VERSION 5.7 ;
  NOWIREEXTENSIONATPIN ON ;
  DIVIDERCHAR "/" ;
  BUSBITCHARS "[]" ;
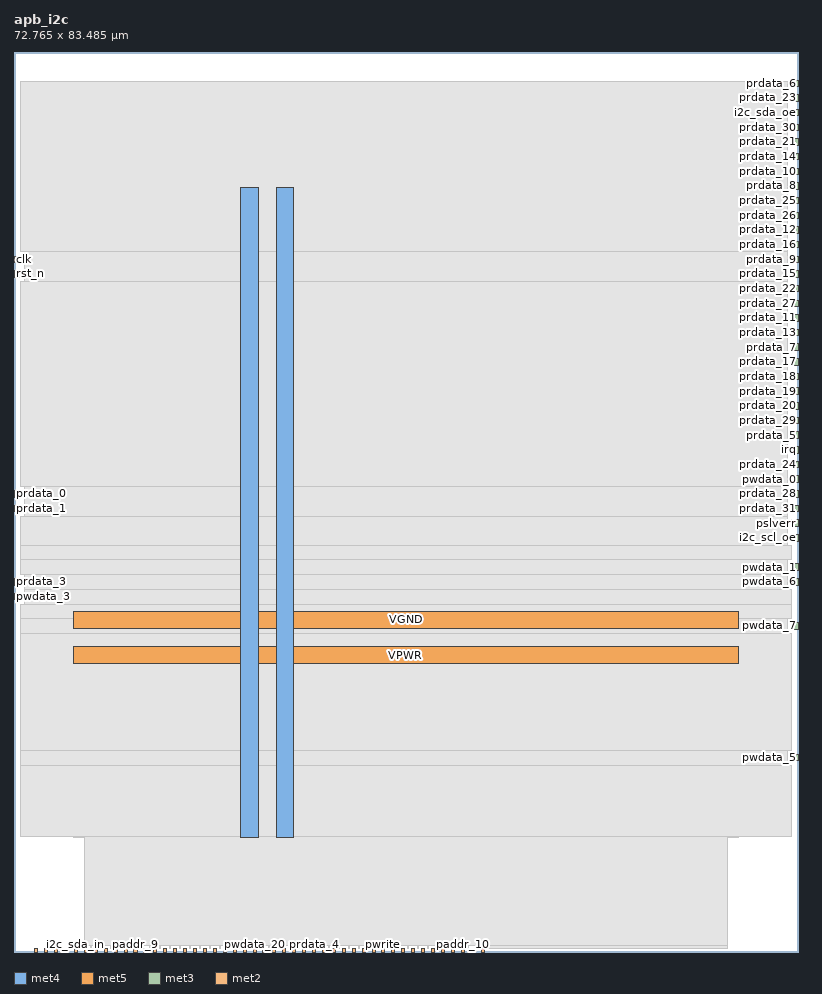
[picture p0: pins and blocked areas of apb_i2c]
MACRO apb_i2c
  CLASS BLOCK ;
  FOREIGN apb_i2c ;
  ORIGIN 0.000 0.000 ;
  SIZE 72.765 BY 83.485 ;
  PIN VGND
    DIRECTION INOUT ;
    USE GROUND ;
    PORT
      LAYER met4 ;
        RECT 24.340 10.640 25.940 70.960 ;
    END
    PORT
      LAYER met5 ;
        RECT 5.520 30.030 67.160 31.630 ;
    END
  END VGND
  PIN VPWR
    DIRECTION INOUT ;
    USE POWER ;
    PORT
      LAYER met4 ;
        RECT 21.040 10.640 22.640 70.960 ;
    END
    PORT
      LAYER met5 ;
        RECT 5.520 26.730 67.160 28.330 ;
    END
  END VPWR
  PIN clk
    DIRECTION INPUT ;
    USE SIGNAL ;
    ANTENNAGATEAREA 1.286700 ;
    ANTENNADIFFAREA 0.434700 ;
    PORT
      LAYER met3 ;
        RECT 0.000 63.960 0.600 64.560 ;
    END
  END clk
  PIN i2c_scl_in
    DIRECTION INPUT ;
    USE SIGNAL ;
    PORT
      LAYER met2 ;
        RECT 2.850 0.000 3.130 0.280 ;
    END
  END i2c_scl_in
  PIN i2c_scl_oe
    DIRECTION OUTPUT ;
    USE SIGNAL ;
    ANTENNAGATEAREA 0.434700 ;
    ANTENNADIFFAREA 0.775300 ;
    PORT
      LAYER met3 ;
        RECT 72.165 38.120 72.765 38.720 ;
    END
  END i2c_scl_oe
  PIN i2c_sda_in
    DIRECTION INPUT ;
    USE SIGNAL ;
    PORT
      LAYER met2 ;
        RECT 5.610 0.000 5.890 0.280 ;
    END
  END i2c_sda_in
  PIN i2c_sda_oe
    DIRECTION OUTPUT ;
    USE SIGNAL ;
    ANTENNAGATEAREA 0.434700 ;
    ANTENNADIFFAREA 0.775300 ;
    PORT
      LAYER met3 ;
        RECT 72.165 77.560 72.765 78.160 ;
    END
  END i2c_sda_oe
  PIN irq
    DIRECTION OUTPUT ;
    USE SIGNAL ;
    ANTENNAGATEAREA 0.434700 ;
    ANTENNADIFFAREA 1.137600 ;
    PORT
      LAYER met3 ;
        RECT 72.165 46.280 72.765 46.880 ;
    END
  END irq
  PIN paddr_0
    DIRECTION INPUT ;
    USE SIGNAL ;
    PORT
      LAYER met2 ;
        RECT 4.690 0.000 4.970 0.280 ;
    END
  END paddr_0
  PIN paddr_1
    DIRECTION INPUT ;
    USE SIGNAL ;
    PORT
      LAYER met2 ;
        RECT 7.450 0.000 7.730 0.280 ;
    END
  END paddr_1
  PIN paddr_10
    DIRECTION INPUT ;
    USE SIGNAL ;
    PORT
      LAYER met2 ;
        RECT 41.490 0.000 41.770 0.280 ;
    END
  END paddr_10
  PIN paddr_11
    DIRECTION INPUT ;
    USE SIGNAL ;
    PORT
      LAYER met2 ;
        RECT 6.530 0.000 6.810 0.280 ;
    END
  END paddr_11
  PIN paddr_2
    DIRECTION INPUT ;
    USE SIGNAL ;
    ANTENNAGATEAREA 0.647700 ;
    ANTENNADIFFAREA 0.434700 ;
    PORT
      LAYER met2 ;
        RECT 39.650 0.000 39.930 0.280 ;
    END
  END paddr_2
  PIN paddr_3
    DIRECTION INPUT ;
    USE SIGNAL ;
    ANTENNAGATEAREA 0.647700 ;
    ANTENNADIFFAREA 0.434700 ;
    PORT
      LAYER met2 ;
        RECT 38.730 0.000 39.010 0.280 ;
    END
  END paddr_3
  PIN paddr_4
    DIRECTION INPUT ;
    USE SIGNAL ;
    ANTENNAGATEAREA 0.647700 ;
    ANTENNADIFFAREA 0.434700 ;
    PORT
      LAYER met2 ;
        RECT 36.890 0.000 37.170 0.280 ;
    END
  END paddr_4
  PIN paddr_5
    DIRECTION INPUT ;
    USE SIGNAL ;
    PORT
      LAYER met2 ;
        RECT 9.290 0.000 9.570 0.280 ;
    END
  END paddr_5
  PIN paddr_6
    DIRECTION INPUT ;
    USE SIGNAL ;
    PORT
      LAYER met2 ;
        RECT 8.370 0.000 8.650 0.280 ;
    END
  END paddr_6
  PIN paddr_7
    DIRECTION INPUT ;
    USE SIGNAL ;
    PORT
      LAYER met2 ;
        RECT 42.410 0.000 42.690 0.280 ;
    END
  END paddr_7
  PIN paddr_8
    DIRECTION INPUT ;
    USE SIGNAL ;
    PORT
      LAYER met2 ;
        RECT 10.210 0.000 10.490 0.280 ;
    END
  END paddr_8
  PIN paddr_9
    DIRECTION INPUT ;
    USE SIGNAL ;
    PORT
      LAYER met2 ;
        RECT 11.130 0.000 11.410 0.280 ;
    END
  END paddr_9
  PIN penable
    DIRECTION INPUT ;
    USE SIGNAL ;
    ANTENNAGATEAREA 0.647700 ;
    ANTENNADIFFAREA 0.434700 ;
    PORT
      LAYER met2 ;
        RECT 35.050 0.000 35.330 0.280 ;
    END
  END penable
  PIN prdata_0
    DIRECTION OUTPUT ;
    USE SIGNAL ;
    ANTENNAGATEAREA 0.434700 ;
    ANTENNADIFFAREA 1.137600 ;
    PORT
      LAYER met3 ;
        RECT 0.000 42.200 0.600 42.800 ;
    END
  END prdata_0
  PIN prdata_1
    DIRECTION OUTPUT ;
    USE SIGNAL ;
    ANTENNAGATEAREA 0.434700 ;
    ANTENNADIFFAREA 1.137600 ;
    PORT
      LAYER met3 ;
        RECT 0.000 40.840 0.600 41.440 ;
    END
  END prdata_1
  PIN prdata_10
    DIRECTION OUTPUT ;
    USE SIGNAL ;
    ANTENNAGATEAREA 0.434700 ;
    ANTENNADIFFAREA 0.775300 ;
    PORT
      LAYER met3 ;
        RECT 72.165 72.120 72.765 72.720 ;
    END
  END prdata_10
  PIN prdata_11
    DIRECTION OUTPUT ;
    USE SIGNAL ;
    ANTENNAGATEAREA 0.434700 ;
    ANTENNADIFFAREA 0.775300 ;
    PORT
      LAYER met3 ;
        RECT 72.165 58.520 72.765 59.120 ;
    END
  END prdata_11
  PIN prdata_12
    DIRECTION OUTPUT ;
    USE SIGNAL ;
    ANTENNAGATEAREA 0.434700 ;
    ANTENNADIFFAREA 0.775300 ;
    PORT
      LAYER met3 ;
        RECT 72.165 66.680 72.765 67.280 ;
    END
  END prdata_12
  PIN prdata_13
    DIRECTION OUTPUT ;
    USE SIGNAL ;
    ANTENNAGATEAREA 0.434700 ;
    ANTENNADIFFAREA 0.775300 ;
    PORT
      LAYER met3 ;
        RECT 72.165 57.160 72.765 57.760 ;
    END
  END prdata_13
  PIN prdata_14
    DIRECTION OUTPUT ;
    USE SIGNAL ;
    ANTENNAGATEAREA 0.434700 ;
    ANTENNADIFFAREA 0.775300 ;
    PORT
      LAYER met3 ;
        RECT 72.165 73.480 72.765 74.080 ;
    END
  END prdata_14
  PIN prdata_15
    DIRECTION OUTPUT ;
    USE SIGNAL ;
    ANTENNAGATEAREA 0.434700 ;
    ANTENNADIFFAREA 0.775300 ;
    PORT
      LAYER met3 ;
        RECT 72.165 62.600 72.765 63.200 ;
    END
  END prdata_15
  PIN prdata_16
    DIRECTION OUTPUT ;
    USE SIGNAL ;
    ANTENNAGATEAREA 0.434700 ;
    ANTENNADIFFAREA 0.775300 ;
    PORT
      LAYER met3 ;
        RECT 72.165 65.320 72.765 65.920 ;
    END
  END prdata_16
  PIN prdata_17
    DIRECTION OUTPUT ;
    USE SIGNAL ;
    ANTENNAGATEAREA 0.434700 ;
    ANTENNADIFFAREA 0.775300 ;
    PORT
      LAYER met3 ;
        RECT 72.165 54.440 72.765 55.040 ;
    END
  END prdata_17
  PIN prdata_18
    DIRECTION OUTPUT ;
    USE SIGNAL ;
    ANTENNAGATEAREA 0.434700 ;
    ANTENNADIFFAREA 0.775300 ;
    PORT
      LAYER met3 ;
        RECT 72.165 53.080 72.765 53.680 ;
    END
  END prdata_18
  PIN prdata_19
    DIRECTION OUTPUT ;
    USE SIGNAL ;
    ANTENNAGATEAREA 0.434700 ;
    ANTENNADIFFAREA 0.775300 ;
    PORT
      LAYER met3 ;
        RECT 72.165 51.720 72.765 52.320 ;
    END
  END prdata_19
  PIN prdata_2
    DIRECTION OUTPUT ;
    USE SIGNAL ;
    ANTENNAGATEAREA 0.434700 ;
    ANTENNADIFFAREA 1.137600 ;
    PORT
      LAYER met2 ;
        RECT 35.970 0.000 36.250 0.280 ;
    END
  END prdata_2
  PIN prdata_20
    DIRECTION OUTPUT ;
    USE SIGNAL ;
    ANTENNAGATEAREA 0.434700 ;
    ANTENNADIFFAREA 0.775300 ;
    PORT
      LAYER met3 ;
        RECT 72.165 50.360 72.765 50.960 ;
    END
  END prdata_20
  PIN prdata_21
    DIRECTION OUTPUT ;
    USE SIGNAL ;
    ANTENNAGATEAREA 0.434700 ;
    ANTENNADIFFAREA 0.775300 ;
    PORT
      LAYER met3 ;
        RECT 72.165 74.840 72.765 75.440 ;
    END
  END prdata_21
  PIN prdata_22
    DIRECTION OUTPUT ;
    USE SIGNAL ;
    ANTENNAGATEAREA 0.434700 ;
    ANTENNADIFFAREA 0.775300 ;
    PORT
      LAYER met3 ;
        RECT 72.165 61.240 72.765 61.840 ;
    END
  END prdata_22
  PIN prdata_23
    DIRECTION OUTPUT ;
    USE SIGNAL ;
    ANTENNAGATEAREA 0.434700 ;
    ANTENNADIFFAREA 0.775300 ;
    PORT
      LAYER met3 ;
        RECT 72.165 78.920 72.765 79.520 ;
    END
  END prdata_23
  PIN prdata_24
    DIRECTION OUTPUT ;
    USE SIGNAL ;
    ANTENNAGATEAREA 0.434700 ;
    ANTENNADIFFAREA 0.775300 ;
    PORT
      LAYER met3 ;
        RECT 72.165 44.920 72.765 45.520 ;
    END
  END prdata_24
  PIN prdata_25
    DIRECTION OUTPUT ;
    USE SIGNAL ;
    ANTENNAGATEAREA 0.434700 ;
    ANTENNADIFFAREA 0.775300 ;
    PORT
      LAYER met3 ;
        RECT 72.165 69.400 72.765 70.000 ;
    END
  END prdata_25
  PIN prdata_26
    DIRECTION OUTPUT ;
    USE SIGNAL ;
    ANTENNAGATEAREA 0.434700 ;
    ANTENNADIFFAREA 0.775300 ;
    PORT
      LAYER met3 ;
        RECT 72.165 68.040 72.765 68.640 ;
    END
  END prdata_26
  PIN prdata_27
    DIRECTION OUTPUT ;
    USE SIGNAL ;
    ANTENNAGATEAREA 0.434700 ;
    ANTENNADIFFAREA 0.775300 ;
    PORT
      LAYER met3 ;
        RECT 72.165 59.880 72.765 60.480 ;
    END
  END prdata_27
  PIN prdata_28
    DIRECTION OUTPUT ;
    USE SIGNAL ;
    ANTENNAGATEAREA 0.434700 ;
    ANTENNADIFFAREA 0.775300 ;
    PORT
      LAYER met3 ;
        RECT 72.165 42.200 72.765 42.800 ;
    END
  END prdata_28
  PIN prdata_29
    DIRECTION OUTPUT ;
    USE SIGNAL ;
    ANTENNAGATEAREA 0.434700 ;
    ANTENNADIFFAREA 0.775300 ;
    PORT
      LAYER met3 ;
        RECT 72.165 49.000 72.765 49.600 ;
    END
  END prdata_29
  PIN prdata_3
    DIRECTION OUTPUT ;
    USE SIGNAL ;
    ANTENNAGATEAREA 0.434700 ;
    ANTENNADIFFAREA 1.137600 ;
    PORT
      LAYER met3 ;
        RECT 0.000 34.040 0.600 34.640 ;
    END
  END prdata_3
  PIN prdata_30
    DIRECTION OUTPUT ;
    USE SIGNAL ;
    ANTENNAGATEAREA 0.434700 ;
    ANTENNADIFFAREA 0.775300 ;
    PORT
      LAYER met3 ;
        RECT 72.165 76.200 72.765 76.800 ;
    END
  END prdata_30
  PIN prdata_31
    DIRECTION OUTPUT ;
    USE SIGNAL ;
    ANTENNAGATEAREA 0.434700 ;
    ANTENNADIFFAREA 0.775300 ;
    PORT
      LAYER met3 ;
        RECT 72.165 40.840 72.765 41.440 ;
    END
  END prdata_31
  PIN prdata_4
    DIRECTION OUTPUT ;
    USE SIGNAL ;
    ANTENNAGATEAREA 0.434700 ;
    ANTENNADIFFAREA 1.137600 ;
    PORT
      LAYER met2 ;
        RECT 27.690 0.000 27.970 0.280 ;
    END
  END prdata_4
  PIN prdata_5
    DIRECTION OUTPUT ;
    USE SIGNAL ;
    ANTENNAGATEAREA 0.434700 ;
    ANTENNADIFFAREA 0.434700 ;
    PORT
      LAYER met3 ;
        RECT 72.165 47.640 72.765 48.240 ;
    END
  END prdata_5
  PIN prdata_6
    DIRECTION OUTPUT ;
    USE SIGNAL ;
    ANTENNAGATEAREA 0.434700 ;
    ANTENNADIFFAREA 0.775300 ;
    PORT
      LAYER met3 ;
        RECT 72.165 80.280 72.765 80.880 ;
    END
  END prdata_6
  PIN prdata_7
    DIRECTION OUTPUT ;
    USE SIGNAL ;
    ANTENNAGATEAREA 0.434700 ;
    ANTENNADIFFAREA 0.775300 ;
    PORT
      LAYER met3 ;
        RECT 72.165 55.800 72.765 56.400 ;
    END
  END prdata_7
  PIN prdata_8
    DIRECTION OUTPUT ;
    USE SIGNAL ;
    ANTENNAGATEAREA 0.434700 ;
    ANTENNADIFFAREA 0.775300 ;
    PORT
      LAYER met3 ;
        RECT 72.165 70.760 72.765 71.360 ;
    END
  END prdata_8
  PIN prdata_9
    DIRECTION OUTPUT ;
    USE SIGNAL ;
    ANTENNAGATEAREA 0.434700 ;
    ANTENNADIFFAREA 0.775300 ;
    PORT
      LAYER met3 ;
        RECT 72.165 63.960 72.765 64.560 ;
    END
  END prdata_9
  PIN pready
    DIRECTION OUTPUT ;
    USE SIGNAL ;
    PORT
      LAYER met2 ;
        RECT 12.050 0.000 12.330 0.280 ;
    END
  END pready
  PIN psel
    DIRECTION INPUT ;
    USE SIGNAL ;
    ANTENNAGATEAREA 0.647700 ;
    ANTENNADIFFAREA 0.434700 ;
    PORT
      LAYER met2 ;
        RECT 28.610 0.000 28.890 0.280 ;
    END
  END psel
  PIN pslverr
    DIRECTION OUTPUT ;
    USE SIGNAL ;
    ANTENNAGATEAREA 0.434700 ;
    ANTENNADIFFAREA 0.775300 ;
    PORT
      LAYER met3 ;
        RECT 72.165 39.480 72.765 40.080 ;
    END
  END pslverr
  PIN pwdata_0
    DIRECTION INPUT ;
    USE SIGNAL ;
    ANTENNAGATEAREA 0.647700 ;
    ANTENNADIFFAREA 0.434700 ;
    PORT
      LAYER met3 ;
        RECT 72.165 43.560 72.765 44.160 ;
    END
  END pwdata_0
  PIN pwdata_1
    DIRECTION INPUT ;
    USE SIGNAL ;
    ANTENNAGATEAREA 0.647700 ;
    ANTENNADIFFAREA 0.434700 ;
    PORT
      LAYER met3 ;
        RECT 72.165 35.400 72.765 36.000 ;
    END
  END pwdata_1
  PIN pwdata_10
    DIRECTION INPUT ;
    USE SIGNAL ;
    PORT
      LAYER met2 ;
        RECT 12.970 0.000 13.250 0.280 ;
    END
  END pwdata_10
  PIN pwdata_11
    DIRECTION INPUT ;
    USE SIGNAL ;
    PORT
      LAYER met2 ;
        RECT 13.890 0.000 14.170 0.280 ;
    END
  END pwdata_11
  PIN pwdata_12
    DIRECTION INPUT ;
    USE SIGNAL ;
    PORT
      LAYER met2 ;
        RECT 14.810 0.000 15.090 0.280 ;
    END
  END pwdata_12
  PIN pwdata_13
    DIRECTION INPUT ;
    USE SIGNAL ;
    PORT
      LAYER met2 ;
        RECT 15.730 0.000 16.010 0.280 ;
    END
  END pwdata_13
  PIN pwdata_14
    DIRECTION INPUT ;
    USE SIGNAL ;
    PORT
      LAYER met2 ;
        RECT 16.650 0.000 16.930 0.280 ;
    END
  END pwdata_14
  PIN pwdata_15
    DIRECTION INPUT ;
    USE SIGNAL ;
    PORT
      LAYER met2 ;
        RECT 17.570 0.000 17.850 0.280 ;
    END
  END pwdata_15
  PIN pwdata_16
    DIRECTION INPUT ;
    USE SIGNAL ;
    PORT
      LAYER met2 ;
        RECT 18.490 0.000 18.770 0.280 ;
    END
  END pwdata_16
  PIN pwdata_17
    DIRECTION INPUT ;
    USE SIGNAL ;
    PORT
      LAYER met2 ;
        RECT 19.410 0.000 19.690 0.280 ;
    END
  END pwdata_17
  PIN pwdata_18
    DIRECTION INPUT ;
    USE SIGNAL ;
    PORT
      LAYER met2 ;
        RECT 20.330 0.000 20.610 0.280 ;
    END
  END pwdata_18
  PIN pwdata_19
    DIRECTION INPUT ;
    USE SIGNAL ;
    PORT
      LAYER met2 ;
        RECT 21.250 0.000 21.530 0.280 ;
    END
  END pwdata_19
  PIN pwdata_2
    DIRECTION INPUT ;
    USE SIGNAL ;
    ANTENNAGATEAREA 0.647700 ;
    ANTENNADIFFAREA 0.434700 ;
    PORT
      LAYER met2 ;
        RECT 37.810 0.000 38.090 0.280 ;
    END
  END pwdata_2
  PIN pwdata_20
    DIRECTION INPUT ;
    USE SIGNAL ;
    PORT
      LAYER met2 ;
        RECT 22.170 0.000 22.450 0.280 ;
    END
  END pwdata_20
  PIN pwdata_21
    DIRECTION INPUT ;
    USE SIGNAL ;
    PORT
      LAYER met2 ;
        RECT 23.090 0.000 23.370 0.280 ;
    END
  END pwdata_21
  PIN pwdata_22
    DIRECTION INPUT ;
    USE SIGNAL ;
    PORT
      LAYER met2 ;
        RECT 29.530 0.000 29.810 0.280 ;
    END
  END pwdata_22
  PIN pwdata_23
    DIRECTION INPUT ;
    USE SIGNAL ;
    PORT
      LAYER met2 ;
        RECT 24.930 0.000 25.210 0.280 ;
    END
  END pwdata_23
  PIN pwdata_24
    DIRECTION INPUT ;
    USE SIGNAL ;
    PORT
      LAYER met2 ;
        RECT 25.850 0.000 26.130 0.280 ;
    END
  END pwdata_24
  PIN pwdata_25
    DIRECTION INPUT ;
    USE SIGNAL ;
    PORT
      LAYER met2 ;
        RECT 26.770 0.000 27.050 0.280 ;
    END
  END pwdata_25
  PIN pwdata_26
    DIRECTION INPUT ;
    USE SIGNAL ;
    PORT
      LAYER met2 ;
        RECT 33.210 0.000 33.490 0.280 ;
    END
  END pwdata_26
  PIN pwdata_27
    DIRECTION INPUT ;
    USE SIGNAL ;
    PORT
      LAYER met2 ;
        RECT 30.450 0.000 30.730 0.280 ;
    END
  END pwdata_27
  PIN pwdata_28
    DIRECTION INPUT ;
    USE SIGNAL ;
    PORT
      LAYER met2 ;
        RECT 31.370 0.000 31.650 0.280 ;
    END
  END pwdata_28
  PIN pwdata_29
    DIRECTION INPUT ;
    USE SIGNAL ;
    PORT
      LAYER met2 ;
        RECT 32.290 0.000 32.570 0.280 ;
    END
  END pwdata_29
  PIN pwdata_3
    DIRECTION INPUT ;
    USE SIGNAL ;
    ANTENNAGATEAREA 0.647700 ;
    ANTENNADIFFAREA 0.434700 ;
    PORT
      LAYER met3 ;
        RECT 0.000 32.680 0.600 33.280 ;
    END
  END pwdata_3
  PIN pwdata_30
    DIRECTION INPUT ;
    USE SIGNAL ;
    PORT
      LAYER met2 ;
        RECT 43.330 0.000 43.610 0.280 ;
    END
  END pwdata_30
  PIN pwdata_31
    DIRECTION INPUT ;
    USE SIGNAL ;
    PORT
      LAYER met2 ;
        RECT 3.770 0.000 4.050 0.280 ;
    END
  END pwdata_31
  PIN pwdata_4
    DIRECTION INPUT ;
    USE SIGNAL ;
    ANTENNAGATEAREA 0.647700 ;
    ANTENNADIFFAREA 0.434700 ;
    PORT
      LAYER met2 ;
        RECT 24.010 0.000 24.290 0.280 ;
    END
  END pwdata_4
  PIN pwdata_5
    DIRECTION INPUT ;
    USE SIGNAL ;
    ANTENNAGATEAREA 0.647700 ;
    ANTENNADIFFAREA 0.434700 ;
    PORT
      LAYER met3 ;
        RECT 72.165 17.720 72.765 18.320 ;
    END
  END pwdata_5
  PIN pwdata_6
    DIRECTION INPUT ;
    USE SIGNAL ;
    ANTENNAGATEAREA 0.647700 ;
    ANTENNADIFFAREA 0.434700 ;
    PORT
      LAYER met3 ;
        RECT 72.165 34.040 72.765 34.640 ;
    END
  END pwdata_6
  PIN pwdata_7
    DIRECTION INPUT ;
    USE SIGNAL ;
    ANTENNAGATEAREA 0.647700 ;
    ANTENNADIFFAREA 0.434700 ;
    PORT
      LAYER met3 ;
        RECT 72.165 29.960 72.765 30.560 ;
    END
  END pwdata_7
  PIN pwdata_8
    DIRECTION INPUT ;
    USE SIGNAL ;
    PORT
      LAYER met2 ;
        RECT 1.930 0.000 2.210 0.280 ;
    END
  END pwdata_8
  PIN pwdata_9
    DIRECTION INPUT ;
    USE SIGNAL ;
    PORT
      LAYER met2 ;
        RECT 40.570 0.000 40.850 0.280 ;
    END
  END pwdata_9
  PIN pwrite
    DIRECTION INPUT ;
    USE SIGNAL ;
    ANTENNAGATEAREA 0.647700 ;
    ANTENNADIFFAREA 0.434700 ;
    PORT
      LAYER met2 ;
        RECT 34.130 0.000 34.410 0.280 ;
    END
  END pwrite
  PIN rst_n
    DIRECTION INPUT ;
    USE SIGNAL ;
    ANTENNAGATEAREA 0.647700 ;
    ANTENNADIFFAREA 0.434700 ;
    PORT
      LAYER met3 ;
        RECT 0.000 62.600 0.600 63.200 ;
    END
  END rst_n
  OBS
      LAYER nwell ;
        RECT 5.330 10.795 67.350 70.805 ;
      LAYER li1 ;
        RECT 5.520 10.795 67.160 70.805 ;
      LAYER met1 ;
        RECT 5.520 10.640 67.160 73.400 ;
      LAYER met2 ;
        RECT 6.530 0.560 66.150 80.765 ;
        RECT 7.090 0.280 7.170 0.560 ;
        RECT 8.010 0.280 8.090 0.560 ;
        RECT 8.930 0.280 9.010 0.560 ;
        RECT 9.850 0.280 9.930 0.560 ;
        RECT 10.770 0.280 10.850 0.560 ;
        RECT 11.690 0.280 11.770 0.560 ;
        RECT 12.610 0.280 12.690 0.560 ;
        RECT 13.530 0.280 13.610 0.560 ;
        RECT 14.450 0.280 14.530 0.560 ;
        RECT 15.370 0.280 15.450 0.560 ;
        RECT 16.290 0.280 16.370 0.560 ;
        RECT 17.210 0.280 17.290 0.560 ;
        RECT 18.130 0.280 18.210 0.560 ;
        RECT 19.050 0.280 19.130 0.560 ;
        RECT 19.970 0.280 20.050 0.560 ;
        RECT 20.890 0.280 20.970 0.560 ;
        RECT 21.810 0.280 21.890 0.560 ;
        RECT 22.730 0.280 22.810 0.560 ;
        RECT 23.650 0.280 23.730 0.560 ;
        RECT 24.570 0.280 24.650 0.560 ;
        RECT 25.490 0.280 25.570 0.560 ;
        RECT 26.410 0.280 26.490 0.560 ;
        RECT 27.330 0.280 27.410 0.560 ;
        RECT 28.250 0.280 28.330 0.560 ;
        RECT 29.170 0.280 29.250 0.560 ;
        RECT 30.090 0.280 30.170 0.560 ;
        RECT 31.010 0.280 31.090 0.560 ;
        RECT 31.930 0.280 32.010 0.560 ;
        RECT 32.850 0.280 32.930 0.560 ;
        RECT 33.770 0.280 33.850 0.560 ;
        RECT 34.690 0.280 34.770 0.560 ;
        RECT 35.610 0.280 35.690 0.560 ;
        RECT 36.530 0.280 36.610 0.560 ;
        RECT 37.450 0.280 37.530 0.560 ;
        RECT 38.370 0.280 38.450 0.560 ;
        RECT 39.290 0.280 39.370 0.560 ;
        RECT 40.210 0.280 40.290 0.560 ;
        RECT 41.130 0.280 41.210 0.560 ;
        RECT 42.050 0.280 42.130 0.560 ;
        RECT 42.970 0.280 43.050 0.560 ;
        RECT 43.890 0.280 66.150 0.560 ;
      LAYER met3 ;
        RECT 0.600 64.960 71.765 80.745 ;
        RECT 1.000 62.200 71.765 64.960 ;
        RECT 0.600 43.200 71.765 62.200 ;
        RECT 1.000 40.440 71.765 43.200 ;
        RECT 0.600 37.720 71.765 40.440 ;
        RECT 0.600 36.400 72.165 37.720 ;
        RECT 0.600 35.040 71.765 36.400 ;
        RECT 1.000 33.640 71.765 35.040 ;
        RECT 1.000 32.280 72.165 33.640 ;
        RECT 0.600 30.960 72.165 32.280 ;
        RECT 0.600 29.560 71.765 30.960 ;
        RECT 0.600 18.720 72.165 29.560 ;
        RECT 0.600 17.320 71.765 18.720 ;
        RECT 0.600 10.715 72.165 17.320 ;
  END
END apb_i2c
END LIBRARY

